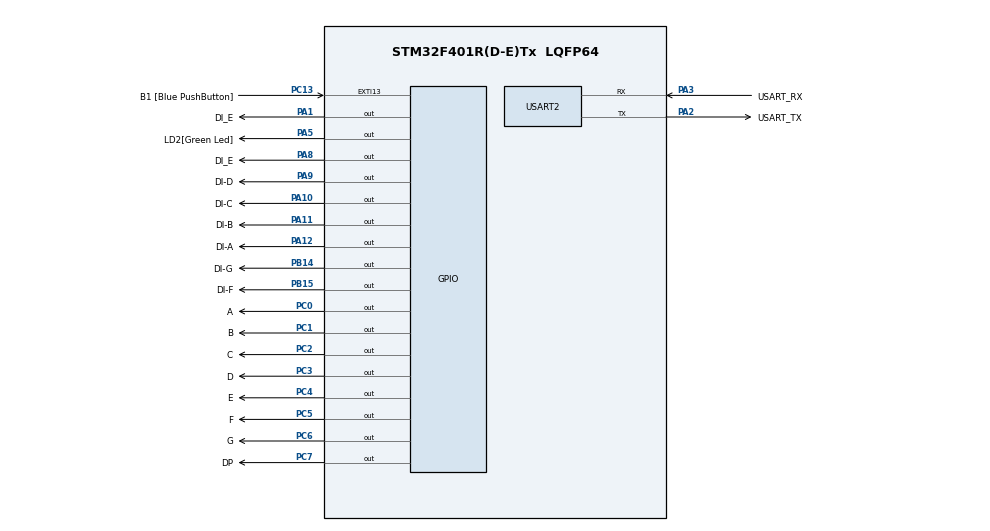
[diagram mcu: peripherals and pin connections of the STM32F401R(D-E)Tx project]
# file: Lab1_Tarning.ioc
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Mcu.Family=STM32F4
Mcu.Name=STM32F401R(D-E)Tx
Mcu.Package=LQFP64
<<<<<<< HEAD
=======
>>>>>>> 3747a35975bc5e230a40e06f4ca24fadc56bda0c
<<<<<<< HEAD
=======
>>>>>>> 3747a35975bc5e230a40e06f4ca24fadc56bda0c
NVIC.PriorityGroup=NVIC_PRIORITYGROUP_0
PA1.GPIO_Label=DI_E
PA1.Signal=GPIO_Output
PA10.GPIO_Label=DI-C
PA10.Signal=GPIO_Output
PA11.GPIO_Label=DI-B
PA11.Signal=GPIO_Output
PA12.GPIO_Label=DI-A
PA12.Signal=GPIO_Output
PA13.GPIO_Label=TMS
PA13.Mode=Serial_Wire
PA13.Signal=SYS_JTMS-SWDIO
PA14.GPIO_Label=TCK
PA14.Mode=Serial_Wire
PA14.Signal=SYS_JTCK-SWCLK
PA2.GPIO_Label=USART_TX
PA2.GPIO_Mode=GPIO_MODE_AF_PP
PA2.GPIO_PuPd=GPIO_NOPULL
PA2.GPIO_Speed=GPIO_SPEED_FREQ_LOW
PA2.Mode=Asynchronous
PA2.Signal=USART2_TX
PA3.GPIO_Label=USART_RX
PA3.GPIO_Mode=GPIO_MODE_AF_PP
PA3.GPIO_PuPd=GPIO_NOPULL
PA3.GPIO_Speed=GPIO_SPEED_FREQ_LOW
PA3.Mode=Asynchronous
PA3.Signal=USART2_RX
PA5.GPIO_Label=LD2[Green Led]
PA5.Signal=GPIO_Output
<<<<<<< HEAD
=======
PA8.GPIO_Label=DI_E
PA8.Signal=GPIO_Output
>>>>>>> 3747a35975bc5e230a40e06f4ca24fadc56bda0c
PA9.GPIO_Label=DI-D
PA9.Signal=GPIO_Output
PB14.GPIO_Label=DI-G
PB14.Signal=GPIO_Output
PB15.GPIO_Label=DI-F
PB15.Signal=GPIO_Output
PB3.GPIO_Label=SWO
PB3.Signal=SYS_JTDO-SWO
PC0.GPIO_Label=A
PC0.Signal=GPIO_Output
PC1.GPIO_Label=B
PC1.Signal=GPIO_Output
PC13-ANTI_TAMP.GPIO_Label=B1 [Blue PushButton]
PC13-ANTI_TAMP.GPIO_ModeDefaultEXTI=GPIO_MODE_IT_FALLING
PC13-ANTI_TAMP.GPIO_PuPd=GPIO_NOPULL
PC13-ANTI_TAMP.Signal=GPXTI13
PC14-OSC32_IN.Mode=LSE-External-Oscillator
PC14-OSC32_IN.Signal=RCC_OSC32_IN
PC15-OSC32_OUT.Mode=LSE-External-Oscillator
PC15-OSC32_OUT.Signal=RCC_OSC32_OUT
PC2.GPIO_Label=C
PC2.Signal=GPIO_Output
PC3.GPIO_Label=D
PC3.Signal=GPIO_Output
PC4.GPIO_Label=E
PC4.Signal=GPIO_Output
PC5.GPIO_Label=F
PC5.Signal=GPIO_Output
PC6.GPIO_Label=G
PC6.Signal=GPIO_Output
PC7.GPIO_Label=DP
PC7.Signal=GPIO_Output
PH0\ -\ OSC_IN.Mode=HSE-External-Clock-Source
PH0\ -\ OSC_IN.Signal=RCC_OSC_IN
PH1\ -\ OSC_OUT.Mode=HSE-External-Clock-Source
PH1\ -\ OSC_OUT.Signal=RCC_OSC_OUT
ProjectManager.HeapSize=0x200
ProjectManager.StackSize=0x400
ProjectManager.TargetToolchain=STM32CubeIDE
USART2.VirtualMode=VM_ASYNC
board=NUCLEO-F401RE

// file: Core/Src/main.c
/* USER CODE BEGIN Header */
/**
  ******************************************************************************
  * @file           : main.c
  * @brief          : Main program body
  ******************************************************************************
  * @attention
  *
  * Copyright (c) 2024 STMicroelectronics.
  * All rights reserved.
  *
  * This software is licensed under terms that can be found in the LICENSE file
  * in the root directory of this software component.
  * If no LICENSE file comes with this software, it is provided AS-IS.
  *
  ******************************************************************************
  */
/* USER CODE END Header */
#include "main.h"

UART_HandleTypeDef huart2;

void SystemClock_Config(void);
static void MX_GPIO_Init(void);
static void MX_USART2_UART_Init(void);
/* USER CODE BEGIN PFP */
int is_blue_button_pressed();
void put_die_dots(uint8_t die_nbr);
/* USER CODE END PFP */

/* USER CODE BEGIN 0 */
//returns 1 if blue button is pressed
//returns 0 if blue button is unpressed'
int is_blue_button_pressed()
{
	uint32_t reg_reading = GPIOC->IDR;
	uint16_t blue_button = 1 << 13;

	int bitValue = (reg_reading & blue_button) ? 1 : 0;
	if(bitValue)
	{
		return 0;
	}
	else
	{
		return 1;
	}

}

void put_die_dots(uint8_t die_nbr)
{
	//turn of all leds
	HAL_GPIO_WritePin(DI_A_GPIO_Port, DI_A_Pin, GPIO_PIN_RESET);
	HAL_GPIO_WritePin(DI_F_GPIO_Port, DI_F_Pin, GPIO_PIN_RESET);
	HAL_GPIO_WritePin(DI_B_GPIO_Port, DI_B_Pin, GPIO_PIN_RESET);
	HAL_GPIO_WritePin(DI_G_GPIO_Port, DI_G_Pin, GPIO_PIN_RESET);
	HAL_GPIO_WritePin(DI_C_GPIO_Port, DI_C_Pin, GPIO_PIN_RESET);
	HAL_GPIO_WritePin(DI_D_GPIO_Port, DI_D_Pin, GPIO_PIN_RESET);
	HAL_GPIO_WritePin(DI_E_GPIO_Port, DI_E_Pin, GPIO_PIN_RESET);

	//HAL_GPIO_WritePin(GPIOA, GPIO_PIN_8, GPIO_PIN_RESET);
	//switch case
	switch (die_nbr) {
		case 1:
			//uint16_t 	PA_8_pin = 0x01 << 8;
			//HAL_GPIO_WritePin(GPIOA, GPIO_PIN_1, GPIO_PIN_SET);
			HAL_GPIO_WritePin(DI_E_GPIO_Port, DI_E_Pin, GPIO_PIN_SET);
			break;

		case 2:
			HAL_GPIO_WritePin(DI_A_GPIO_Port, DI_A_Pin, GPIO_PIN_SET);
			HAL_GPIO_WritePin(DI_G_GPIO_Port, DI_G_Pin, GPIO_PIN_SET);
			break;

		case 3:
			HAL_GPIO_WritePin(DI_E_GPIO_Port, DI_E_Pin, GPIO_PIN_SET);
			HAL_GPIO_WritePin(DI_A_GPIO_Port, DI_A_Pin, GPIO_PIN_SET);
			HAL_GPIO_WritePin(DI_G_GPIO_Port, DI_G_Pin, GPIO_PIN_SET);

		case 4:
			HAL_GPIO_WritePin(DI_A_GPIO_Port, DI_A_Pin, GPIO_PIN_SET);
			HAL_GPIO_WritePin(DI_F_GPIO_Port, DI_F_Pin, GPIO_PIN_SET);
			HAL_GPIO_WritePin(DI_B_GPIO_Port, DI_B_Pin, GPIO_PIN_SET);
			HAL_GPIO_WritePin(DI_G_GPIO_Port, DI_G_Pin, GPIO_PIN_SET);

		case 5:
			HAL_GPIO_WritePin(DI_A_GPIO_Port, DI_A_Pin, GPIO_PIN_SET);
			HAL_GPIO_WritePin(DI_F_GPIO_Port, DI_F_Pin, GPIO_PIN_SET);
			HAL_GPIO_WritePin(DI_B_GPIO_Port, DI_B_Pin, GPIO_PIN_SET);
			HAL_GPIO_WritePin(DI_G_GPIO_Port, DI_G_Pin, GPIO_PIN_SET);
			HAL_GPIO_WritePin(DI_E_GPIO_Port, DI_E_Pin, GPIO_PIN_SET);

		case 6:
			HAL_GPIO_WritePin(DI_A_GPIO_Port, DI_A_Pin, GPIO_PIN_SET);
			HAL_GPIO_WritePin(DI_F_GPIO_Port, DI_F_Pin, GPIO_PIN_SET);
			HAL_GPIO_WritePin(DI_B_GPIO_Port, DI_B_Pin, GPIO_PIN_SET);
			HAL_GPIO_WritePin(DI_G_GPIO_Port, DI_G_Pin, GPIO_PIN_SET);
			HAL_GPIO_WritePin(DI_C_GPIO_Port, DI_C_Pin, GPIO_PIN_SET);
			HAL_GPIO_WritePin(DI_D_GPIO_Port, DI_D_Pin, GPIO_PIN_SET);
		default:
			HAL_GPIO_WritePin(DI_A_GPIO_Port, DI_A_Pin, GPIO_PIN_SET);
			HAL_GPIO_WritePin(DI_F_GPIO_Port, DI_F_Pin, GPIO_PIN_SET);
			HAL_GPIO_WritePin(DI_B_GPIO_Port, DI_B_Pin, GPIO_PIN_SET);
			HAL_GPIO_WritePin(DI_G_GPIO_Port, DI_G_Pin, GPIO_PIN_SET);
			HAL_GPIO_WritePin(DI_C_GPIO_Port, DI_C_Pin, GPIO_PIN_SET);
			HAL_GPIO_WritePin(DI_D_GPIO_Port, DI_D_Pin, GPIO_PIN_SET);
			HAL_GPIO_WritePin(DI_E_GPIO_Port, DI_E_Pin, GPIO_PIN_SET);
	}

}

/* USER CODE END 0 */

int main(void)
{

  /* MCU Configuration--------------------------------------------------------*/

  /* Reset of all peripherals, Initializes the Flash interface and the Systick. */
  HAL_Init();

  /* Configure the system clock */
  SystemClock_Config();

  /* Initialize all configured peripherals */
  MX_GPIO_Init();
  MX_USART2_UART_Init();
  /* USER CODE BEGIN 2 */
  //for loop to test if the functionality works
  for (int i=0; i<7; i++) {
	  put_die_dots(i);
	  HAL_Delay(1000);
  }

  /* USER CODE END 2 */

  /* Infinite loop */
  /* USER CODE BEGIN WHILE */
  int pressed = 0;
  while (1)
  {
    /* USER CODE END WHILE */
	  //pressed = HAL_GPIO_ReadPin(B1_GPIO_Port, B1_Pin);
	  pressed = is_blue_button_pressed();

	  uint8_t die_value = 1; // 1 <= die value <= 6

	  if (pressed)
	  {
		  HAL_GPIO_WritePin(LD2_GPIO_Port, LD2_Pin, GPIO_PIN_SET);

		  if (die_value == 6){
			  die_value = 1;
		  } else {
			  HAL_Delay(100); //(FOR TESTING)
			  die_value++;
		  }
	  }
	  else
	  {
		  GPIO_TypeDef* Id2_gpio    = GPIOA;
		  uint16_t      Id2_pin_nbr = 5;
		  uint16_t 	    Id2_pin     = 0x01 << Id2_pin_nbr;
		  HAL_GPIO_WritePin(Id2_gpio, Id2_pin, GPIO_PIN_RESET);
		  put_die_dots(die_value);
	  }
  }
}

void SystemClock_Config(void)
{
  RCC_OscInitTypeDef RCC_OscInitStruct = {0};
  RCC_ClkInitTypeDef RCC_ClkInitStruct = {0};

  /** Configure the main internal regulator output voltage
  */
  __HAL_RCC_PWR_CLK_ENABLE();
  __HAL_PWR_VOLTAGESCALING_CONFIG(PWR_REGULATOR_VOLTAGE_SCALE2);

  /** Initializes the RCC Oscillators according to the specified parameters
  * in the RCC_OscInitTypeDef structure.
  */
  RCC_OscInitStruct.OscillatorType = RCC_OSCILLATORTYPE_HSI;
  RCC_OscInitStruct.HSIState = RCC_HSI_ON;
  RCC_OscInitStruct.HSICalibrationValue = RCC_HSICALIBRATION_DEFAULT;
  RCC_OscInitStruct.PLL.PLLState = RCC_PLL_ON;
  RCC_OscInitStruct.PLL.PLLSource = RCC_PLLSOURCE_HSI;
  RCC_OscInitStruct.PLL.PLLM = 16;
  RCC_OscInitStruct.PLL.PLLN = 336;
  RCC_OscInitStruct.PLL.PLLP = RCC_PLLP_DIV4;
  RCC_OscInitStruct.PLL.PLLQ = 7;
  if (HAL_RCC_OscConfig(&RCC_OscInitStruct) != HAL_OK)
  {
    Error_Handler();
  }

  /** Initializes the CPU, AHB and APB buses clocks
  */
  RCC_ClkInitStruct.ClockType = RCC_CLOCKTYPE_HCLK|RCC_CLOCKTYPE_SYSCLK
                              |RCC_CLOCKTYPE_PCLK1|RCC_CLOCKTYPE_PCLK2;
  RCC_ClkInitStruct.SYSCLKSource = RCC_SYSCLKSOURCE_PLLCLK;
  RCC_ClkInitStruct.AHBCLKDivider = RCC_SYSCLK_DIV1;
  RCC_ClkInitStruct.APB1CLKDivider = RCC_HCLK_DIV2;
  RCC_ClkInitStruct.APB2CLKDivider = RCC_HCLK_DIV1;

  if (HAL_RCC_ClockConfig(&RCC_ClkInitStruct, FLASH_LATENCY_2) != HAL_OK)
  {
    Error_Handler();
  }
}

static void MX_USART2_UART_Init(void)
{

  huart2.Instance = USART2;
  huart2.Init.BaudRate = 115200;
  huart2.Init.WordLength = UART_WORDLENGTH_8B;
  huart2.Init.StopBits = UART_STOPBITS_1;
  huart2.Init.Parity = UART_PARITY_NONE;
  huart2.Init.Mode = UART_MODE_TX_RX;
  huart2.Init.HwFlowCtl = UART_HWCONTROL_NONE;
  huart2.Init.OverSampling = UART_OVERSAMPLING_16;
  if (HAL_UART_Init(&huart2) != HAL_OK)
  {
    Error_Handler();
  }

}

static void MX_GPIO_Init(void)
{
  GPIO_InitTypeDef GPIO_InitStruct = {0};

  /* GPIO Ports Clock Enable */
  __HAL_RCC_GPIOC_CLK_ENABLE();
  __HAL_RCC_GPIOH_CLK_ENABLE();
  __HAL_RCC_GPIOA_CLK_ENABLE();
  __HAL_RCC_GPIOB_CLK_ENABLE();

  /*Configure GPIO pin Output Level */
  HAL_GPIO_WritePin(LD2_GPIO_Port, LD2_Pin, GPIO_PIN_RESET);

  /*Configure GPIO pin : B1_Pin */
  GPIO_InitStruct.Pin = B1_Pin;
  GPIO_InitStruct.Mode = GPIO_MODE_IT_FALLING;
  GPIO_InitStruct.Pull = GPIO_NOPULL;
  HAL_GPIO_Init(B1_GPIO_Port, &GPIO_InitStruct);

  /*Configure GPIO pin : LD2_Pin */
  GPIO_InitStruct.Pin = LD2_Pin;
  GPIO_InitStruct.Mode = GPIO_MODE_OUTPUT_PP;
  GPIO_InitStruct.Pull = GPIO_NOPULL;
  GPIO_InitStruct.Speed = GPIO_SPEED_FREQ_LOW;
  HAL_GPIO_Init(LD2_GPIO_Port, &GPIO_InitStruct);

}

void Error_Handler(void)
{
  __disable_irq();
  while (1)
  {
  }
}
